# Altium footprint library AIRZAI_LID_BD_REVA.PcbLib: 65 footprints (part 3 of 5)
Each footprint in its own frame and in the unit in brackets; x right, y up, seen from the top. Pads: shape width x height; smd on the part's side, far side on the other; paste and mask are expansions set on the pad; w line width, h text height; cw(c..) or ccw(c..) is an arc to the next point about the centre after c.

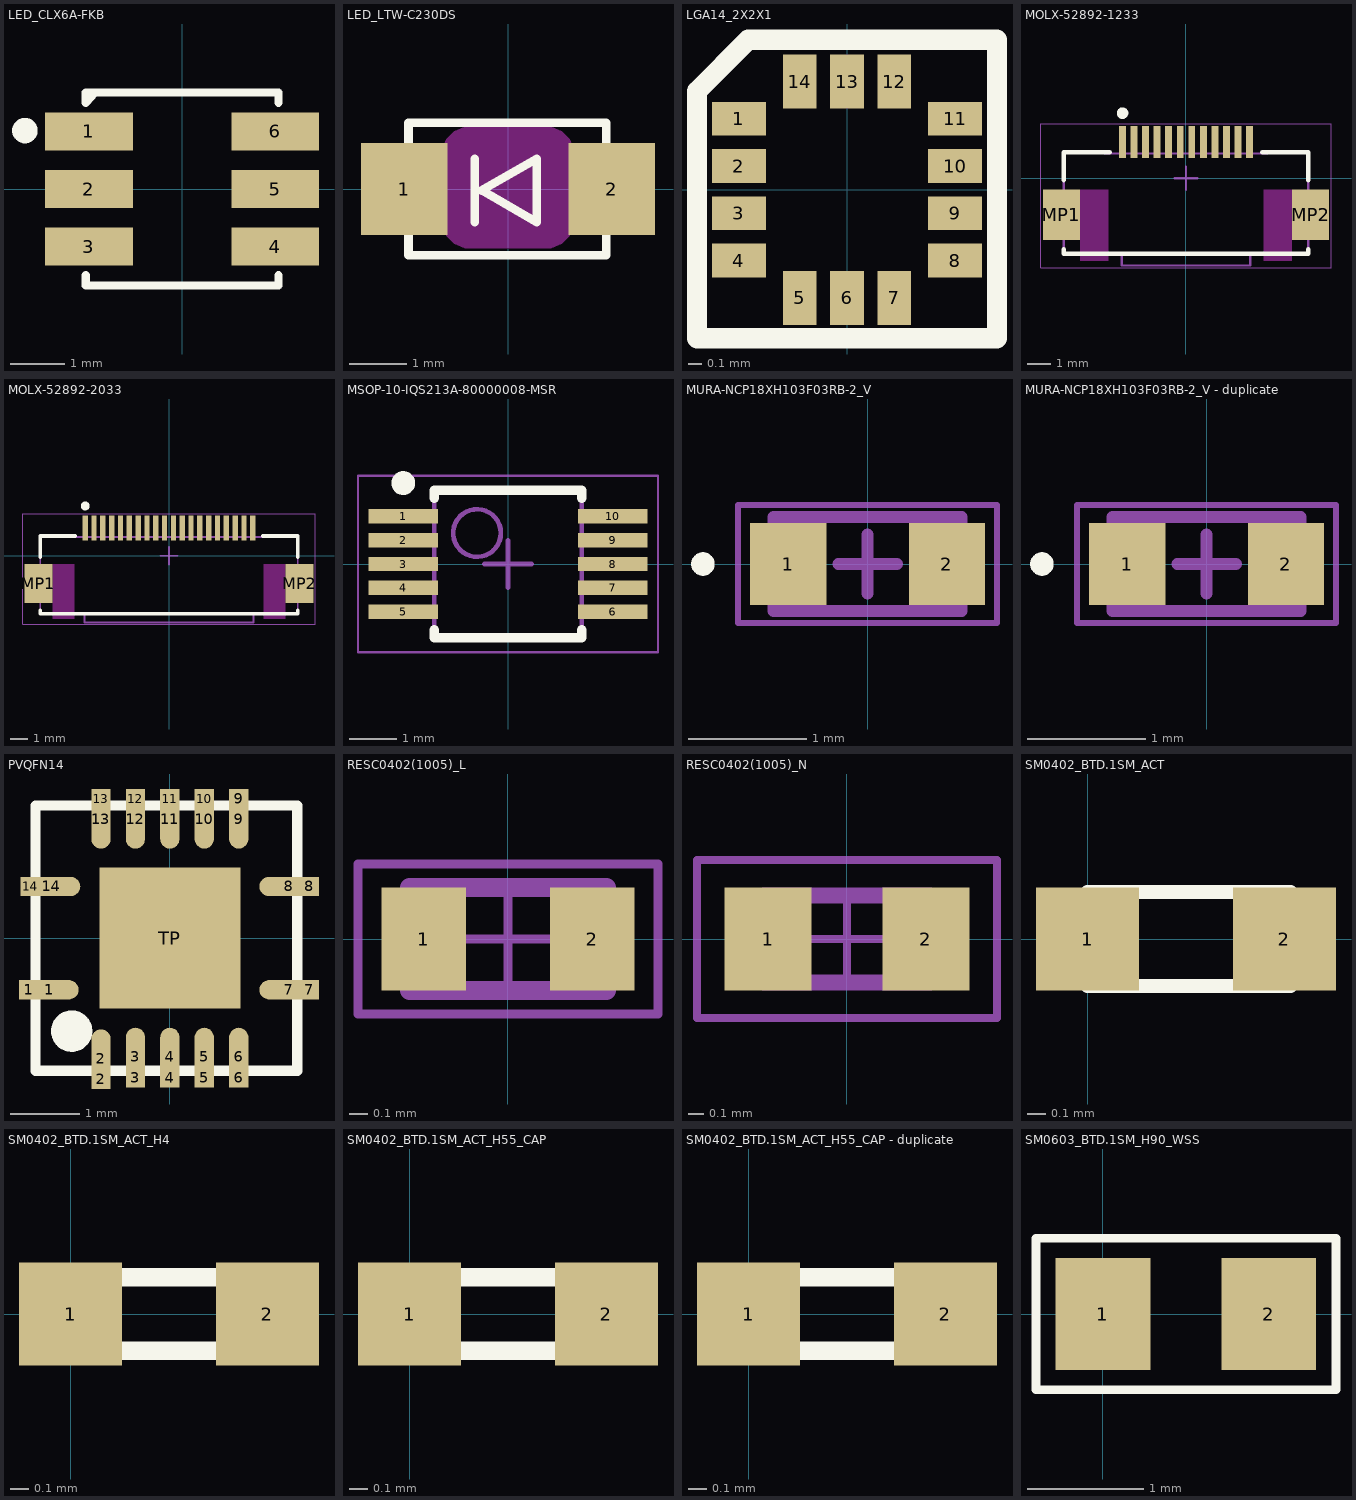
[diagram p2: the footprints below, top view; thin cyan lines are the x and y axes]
## LED_CLX6A-FKB [mm] "CREE LED 3 IN 1"
height 2.9
pads (6):
  rect 1.6x0.7 smd paste-0.1 mask+0.07: 1(-1.7,1.05) 2(-1.7,0) 3(-1.7,-1.05) 4(1.7,-1.05) 5(1.7,0) 6(1.7,1.05)
Top Overlay:
  circle w0.25: c-2.87,1.067 r0.108
  lines w0.15: -1.76,-1.575 -1.76,-1.76 1.76,-1.76 1.76,-1.575 ; -1.76,1.575 -1.76,1.76 1.76,1.76 1.76,1.575 ; -1.743,1.59 -1.6,1.75
3D body: height 2.89, standoff 0, extent -1.75,-1.75 1.75,1.75
3D body: height 1.7, standoff 0, extent -1.8,-0.3 1.8,0.3
3D body: height 1.7, standoff 0, extent -1.8,0.75 1.8,1.35
3D body: height 1.7, standoff 0, extent -1.8,-1.325 1.8,-0.725
3D body: height 2.9, standoff 0, extent -1.76,1.49 -1.49,1.76

## LED_LTW-C230DS [mm] "REVERSE MOUNT CHIP LED"
height 1.1
pads (2):
  rect 1.5x1.6 smd paste-0.1 mask+0.07: 1(-1.8,0) 2(1.8,0)
Top Overlay:
  lines w0.15: -0.575,-0.575 -0.575,0.525 ; -1.725,-1.15 -1.725,1.15 1.7,1.15 1.7,-1.15 -1.725,-1.15 ; -0.453,-0.025 0.5,0.525 0.5,-0.575 -0.453,-0.025
Keep-Out Layer:
  board cut-out: -0.65,-1.025 -0.749,-1.025 -0.933,-0.949 -1.074,-0.808 -1.15,-0.624 -1.15,-0.525 -1.15,0.575 -1.15,0.674 -1.074,0.858 -0.933,0.999 -0.749,1.075 -0.65,1.075 0.65,1.075 0.749,1.075 0.933,0.999 1.074,0.858 1.15,0.674 1.15,0.575 1.15,-0.525 1.15,-0.624 1.074,-0.808 0.933,-0.949 0.749,-1.025 0.65,-1.025
3D body: height 0, standoff -1.1, extent -0.675,-0.8 0.825,0.8
3D body: height 0.28, standoff 0, extent -1.6,-0.8 1.6,0.8

## LGA14_2X2X1 [mm]
height 1
pads (14):
  rect 0.4x0.25 smd paste+0 mask+0: 1(-0.8,0.525) 2(-0.8,0.175) 3(-0.8,-0.175) 4(-0.8,-0.525) 8(0.8,-0.525) 9(0.8,-0.175) 10(0.8,0.175) 11(0.8,0.525)
  rect 0.25x0.4 smd paste+0 mask+0: 5(-0.35,-0.8) 6(0,-0.8) 7(0.35,-0.8) 12(0.35,0.8) 13(0,0.8) 14(-0.35,0.8)
Top Overlay:
  lines w0.15: -1.11,-1.1 1.11,-1.1 1.11,1.11 -0.73,1.11 -1.11,0.73 -1.11,-1.1
3D body: height 1, standoff 0, extent -1,-1 1,1

## MOLX-52892-1233 [mm] "FPC Connector, 12-Leads, Right Angle, Pitch 0.5 mm, Mated Height 2.0 mm, SMT"
height 2.052
pads (14):
  rect 0.3x1.4 smd: 1(-2.75,1.575) 2(-2.25,1.575) 3(-1.75,1.575) 4(-1.25,1.575) 5(-0.75,1.575) 6(-0.25,1.575) 7(0.25,1.575) 8(0.75,1.575) 9(1.25,1.575) 10(1.75,1.575) 11(2.25,1.575) 12(2.75,1.575)
  rect 1.6x2.2 smd: MP1(-5.4,-1.575) MP2(5.4,-1.575)
Top Overlay:
  circle w0.25: c-2.75,2.825 r0.125
  lines w0.2: -5.3,-3.075 -5.3,-3.275 5.3,-3.275 5.3,-3.075 ; -5.3,-0.075 -5.3,1.125 -3.3,1.125 ; 3.3,1.125 5.3,1.125 5.3,-0.075
Keep-Out Layer:
  rectangle: -4.6,-3.575 -3.35,-0.475
  rectangle: 3.35,-3.575 4.6,-0.475
Mechanical 13:
  lines w0.1: -5.3,-3.275 -2.785,-3.275 -2.785,-3.775 2.785,-3.775 2.785,-3.275 5.3,-3.275 5.3,1.125 3.5,1.125 3.5,1.075 -3.5,1.075 -3.5,1.125 -5.3,1.125 -5.3,-3.275
Mechanical 15:
  lines w0.05: -6.3,-3.875 -6.3,2.375 6.3,2.375 6.3,-3.875 -6.3,-3.875
  lines w0.1: -0.5,0 0.5,0 ; 0,-0.5 0,0.5
3D body "528921233.stp": height 2.05, standoff 0.01, extent -5.7,-3.775 5.7,1.725

## MOLX-52892-2033 [mm] "FPC Connector, 20-Leads, Right Angle, Pitch 0.5 mm, Mated Height 2.0 mm, SMT"
height 2.052
pads (22):
  rect 0.3x1.4 smd: 1(-4.75,1.575) 2(-4.25,1.575) 3(-3.75,1.575) 4(-3.25,1.575) 5(-2.75,1.575) 6(-2.25,1.575) 7(-1.75,1.575) 8(-1.25,1.575) 9(-0.75,1.575) 10(-0.25,1.575) 11(0.25,1.575) 12(0.75,1.575) 13(1.25,1.575) 14(1.75,1.575) 15(2.25,1.575) 16(2.75,1.575) 17(3.25,1.575) 18(3.75,1.575) 19(4.25,1.575) 20(4.75,1.575)
  rect 1.6x2.2 smd: MP1(-7.4,-1.575) MP2(7.4,-1.575)
Top Overlay:
  circle w0.25: c-4.75,2.825 r0.125
  lines w0.2: -7.3,-3.075 -7.3,-3.275 7.3,-3.275 7.3,-3.075 ; -7.3,-0.075 -7.3,1.125 -5.3,1.125 ; 5.3,1.125 7.3,1.125 7.3,-0.075
Keep-Out Layer:
  rectangle: -6.6,-3.575 -5.35,-0.475
  rectangle: 5.35,-3.575 6.6,-0.475
Mechanical 13:
  lines w0.1: -7.3,-3.275 -4.785,-3.275 -4.785,-3.775 4.785,-3.775 4.785,-3.275 7.3,-3.275 7.3,1.125 5.5,1.125 5.5,1.075 -5.5,1.075 -5.5,1.125 -7.3,1.125 -7.3,-3.275
Mechanical 15:
  lines w0.05: -8.3,-3.875 -8.3,2.375 8.3,2.375 8.3,-3.875 -8.3,-3.875
  lines w0.1: -0.5,0 0.5,0 ; 0,-0.5 0,0.5
3D body "528922033.stp": height 2.05, standoff 0.01, extent -7.7,-3.775 7.7,1.725

## MSOP-10-IQS213A-80000008-MSR [mm]
height 0.96
pads (10):
  rect 1.45x0.3 smd mask+0.072: 1(-2.2,1) 2(-2.2,0.5) 3(-2.2,0) 4(-2.2,-0.5) 5(-2.2,-1) 6(2.2,-1) 7(2.2,-0.5) 8(2.2,0) 9(2.2,0.5) 10(2.2,1)
Top Overlay:
  circle w0.25: c-2.2,1.7 r0.125
  lines w0.2: -1.55,-1.378 -1.55,-1.55 1.55,-1.55 1.55,-1.378 ; -1.55,1.378 -1.55,1.55 1.55,1.55 1.55,1.378
Mechanical 13:
  circle w0.1: c-0.65,0.65 r0.5
  lines w0.1: -1.55,-1.55 1.55,-1.55 1.55,1.55 -1.55,1.55 -1.55,-1.55
Mechanical 15:
  lines w0.05: -3.15,-1.85 3.15,-1.85 3.15,1.85 -3.15,1.85 -3.15,-1.85
  lines w0.1: -0.5,0 0.5,0 ; 0,-0.5 0,0.5
3D body "MSOP-10-IQS213A-80000008-MSR.step": height 0.96, standoff 0, extent -2.45,-1.6 2.45,1.6

## MURA-NCP18XH103F03RB-2_V [mm] "Chip, 2-Leads, Body 1.6x0.8mm"
height 0.8
pads (2):
  rect 0.65x0.7 smd: 1(-0.675,0) 2(0.675,0)
Top Overlay:
  circle w0.1: c-1.4,0 r0.05
Mechanical 13:
  lines w0.1: -0.8,-0.4 0.8,-0.4 0.8,0.4 -0.8,0.4 -0.8,-0.4
Mechanical 15:
  lines w0.05: -1.1,-0.5 1.1,-0.5 1.1,0.5 -1.1,0.5 -1.1,-0.5
  lines w0.1: -0.25,0 0.25,0 ; 0,-0.25 0,0.25
3D body: height 0.8, standoff 0, extent -0.8,-0.4 0.8,0.4

## MURA-NCP18XH103F03RB-2_V - duplicate [mm] "Chip, 2-Leads, Body 1.6x0.8mm"
height 0.8
pads (2):
  rect 0.65x0.7 smd: 1(-0.675,0) 2(0.675,0)
Top Overlay:
  circle w0.1: c-1.4,0 r0.05
Mechanical 13:
  lines w0.1: -0.8,-0.4 0.8,-0.4 0.8,0.4 -0.8,0.4 -0.8,-0.4
Mechanical 15:
  lines w0.05: -1.1,-0.5 1.1,-0.5 1.1,0.5 -1.1,0.5 -1.1,-0.5
  lines w0.1: -0.25,0 0.25,0 ; 0,-0.25 0,0.25
3D body: height 0.8, standoff 0, extent -0.8,-0.4 0.8,0.4

## PVQFN14 [mm] "PVQFN 14PIN 3.65X3.65"
height 1
pads (29):
  rect 0.28x0.28 smd paste-0.025 mask+0.07: 1(-2.05,-0.75) 2(-1,-2.05) 3(-0.5,-2.025) 4(0,-2.025) 5(0.5,-2.025) 6(1,-2.025) 7(2.025,-0.75) 8(2.025,0.75) 9(1,2.025) 10(0.5,2.025) 11(0,2.025) 12(-0.5,2.025) 13(-1,2.025) 14(-2.025,0.75)
  rrect100% 0.85x0.28 smd paste-0.025 mask+0.07: 1(-1.75,-0.75) 7(1.725,-0.75) 8(1.725,0.75) 14(-1.725,0.75)
  rrect100% 0.28x0.85 smd paste-0.025 mask+0.07: 2(-1,-1.75) 3(-0.5,-1.725) 4(0,-1.725) 5(0.5,-1.725) 6(1,-1.725) 9(1,1.725) 10(0.5,1.725) 11(0,1.725) 12(-0.5,1.725) 13(-1,1.725)
  rect 2.05x2.05 smd paste-5 mask+0.07: TP(0,0)
Top Overlay:
  circle w0.3: c-1.425,-1.35 r0.15
  lines w0.15: -1.95,-1.925 1.85,-1.925 1.85,1.925 -1.95,1.925 -1.95,-1.925
Top Paste:
  rectangle: -0.95,-0.95 -0.15,-0.15
  rectangle: 0.15,-0.95 0.95,-0.15
  rectangle: 0.15,0.15 0.95,0.95
  rectangle: -0.95,0.15 -0.15,0.95
3D body: height 1, standoff 0, extent -1.825,-1.825 1.75,1.825

## RESC0402(1005)_L [mm] "Chip Resistor, Body 1.0x0.5mm, IPC High Density"
height 0.4
pads (2):
  rect 0.45x0.55 smd: 1(-0.45,0) 2(0.45,0)
Mechanical 13:
  lines w0.1: -0.525,-0.275 -0.525,0.275 0.525,0.275 0.525,-0.275 -0.525,-0.275
Mechanical 15:
  lines w0.05: -0.275,0 0.275,0 ; 0,-0.275 0,0.275 ; -0.8,-0.4 -0.8,0.4 0.8,0.4 0.8,-0.4 -0.8,-0.4
3D body: height 0.4, standoff 0, extent -0.525,-0.275 -0.3,0.275
3D body: height 0.4, standoff 0, extent -0.3,-0.275 0.3,0.275
3D body: height 0.4, standoff 0, extent 0.3,-0.275 0.525,0.275

## RESC0402(1005)_N [mm] "Chip Resistor, Body 1.0x0.5mm, IPC Medium Density"
height 0.4
pads (2):
  rect 0.55x0.65 smd: 1(-0.5,0) 2(0.5,0)
Mechanical 13:
  lines w0.1: -0.525,-0.275 -0.525,0.275 0.525,0.275 0.525,-0.275 -0.525,-0.275
Mechanical 15:
  lines w0.05: -0.275,0 0.275,0 ; 0,-0.275 0,0.275 ; -0.95,-0.5 -0.95,0.5 0.95,0.5 0.95,-0.5 -0.95,-0.5
3D body: height 0.4, standoff 0, extent 0.3,-0.275 0.525,0.275
3D body: height 0.4, standoff 0, extent -0.3,-0.275 0.3,0.275
3D body: height 0.4, standoff 0, extent -0.525,-0.275 -0.3,0.275

## SM0402_BTD.1SM_ACT [mil]
height 275.59
pads (2):
  rect 22x22 smd mask+4: 1(0,0) 2(42,0)
Top Overlay:
  lines w2.99: 0,-10 43.27,-10 43.27,10 0,10 0,-10
3D body: height 23.62, standoff 0, extent -0.98,-9.84 44.29,9.84

## SM0402_BTD.1SM_ACT_H4 [mil]
height 15.75
pads (2):
  rect 22x22 smd mask+4: 1(0,0) 2(42,0)
Top Overlay:
  lines w3.94: 0.98,-7.87 42.32,-7.87 42.32,7.87 0.98,7.87 0.98,-7.87
3D body: height 19.68, standoff 0, extent -0.98,-9.84 44.29,9.84

## SM0402_BTD.1SM_ACT_H55_CAP [mil]
height 21.65
pads (2):
  rect 22x22 smd mask+2.76: 1(0,0) 2(42,0)
Top Overlay:
  lines w3.94: 0.98,-7.87 0.98,7.87 42.32,7.87 42.32,-7.87 0.98,-7.87
3D body: height 25.59, standoff 0, extent -0.98,-9.84 44.29,9.84

## SM0402_BTD.1SM_ACT_H55_CAP - duplicate [mil]
height 21.65
pads (2):
  rect 22x22 smd mask+2.76: 1(0,0) 2(42,0)
Top Overlay:
  lines w3.94: 0.98,-7.87 42.32,-7.87 42.32,7.87 0.98,7.87 0.98,-7.87
3D body: height 25.59, standoff 0, extent -0.98,-9.84 44.29,9.84

## SM0603_BTD.1SM_H90_WSS [mil]
height 35.43
pads (2):
  rect 32x38 smd mask+4: 1(0,0) 2(56,0)
Top Overlay:
  lines w3: -22.64,-25.59 78.74,-25.59 78.74,25.59 -22.64,25.59 -22.64,-25.59
3D body: height 35.43, standoff 0, extent -3.94,-16.73 59.06,16.73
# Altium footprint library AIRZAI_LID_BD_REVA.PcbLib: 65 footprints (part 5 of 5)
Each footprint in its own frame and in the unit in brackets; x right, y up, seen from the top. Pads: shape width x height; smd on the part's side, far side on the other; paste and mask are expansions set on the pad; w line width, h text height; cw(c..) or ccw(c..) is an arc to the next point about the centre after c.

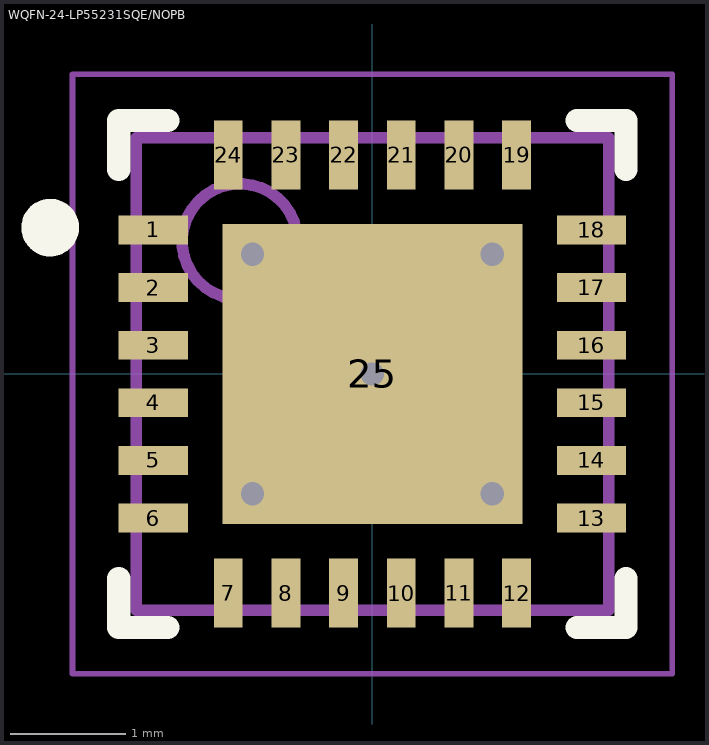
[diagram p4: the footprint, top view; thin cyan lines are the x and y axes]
## WQFN-24-LP55231SQE/NOPB [mm] "QFN, 24-Leads, Body 3.97x3.97mm, Pitch 0.50mm, Thermal Pad 2.60x2.60mm, IPC Medium Density"
height 0.8
pads (25):
  rect 0.6x0.25 smd: 1(-1.9,1.25) 2(-1.9,0.75) 3(-1.9,0.25) 4(-1.9,-0.25) 5(-1.9,-0.75) 6(-1.9,-1.25) 13(1.9,-1.25) 14(1.9,-0.75) 15(1.9,-0.25) 16(1.9,0.25) 17(1.9,0.75) 18(1.9,1.25)
  rect 0.25x0.6 smd: 7(-1.25,-1.9) 8(-0.75,-1.9) 9(-0.25,-1.9) 10(0.25,-1.9) 11(0.75,-1.9) 12(1.25,-1.9) 19(1.25,1.9) 20(0.75,1.9) 21(0.25,1.9) 22(-0.25,1.9) 23(-0.75,1.9) 24(-1.25,1.9)
  rect 2.6x2.6 smd: 25(0,0)
via 0,0 diameter 0.508 hole 0.203
via -1.04,1.04 diameter 0.508 hole 0.203
via 1.04,1.04 diameter 0.508 hole 0.203
via -1.04,-1.04 diameter 0.508 hole 0.203
via 1.04,-1.04 diameter 0.508 hole 0.203
Top Overlay:
  circle w0.25: c-2.794,1.27 r0.125
  lines w0.2: -2.2,-1.775 -2.2,-2.2 -1.775,-2.2 ; -2.2,1.775 -2.2,2.2 -1.775,2.2 ; 1.775,-2.2 2.2,-2.2 2.2,-1.775 ; 1.775,2.2 2.2,2.2 2.2,1.775
Mechanical 13:
  circle w0.1: c-1.15,1.15 r0.5
  lines w0.1: -2.05,-2.05 -2.05,2.05 2.05,2.05 2.05,-2.05 -2.05,-2.05
Mechanical 15:
  lines w0.05: -2.6,-2.6 -2.6,2.6 2.6,2.6 2.6,-2.6 -2.6,-2.6
  lines w0.1: -0.5,0 0.5,0 ; 0,-0.5 0,0.5
3D body "User Library-WQFN-24.STEP": height 0.8, standoff 0, extent -2.01,-2.01 2.01,2.01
